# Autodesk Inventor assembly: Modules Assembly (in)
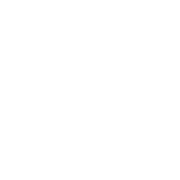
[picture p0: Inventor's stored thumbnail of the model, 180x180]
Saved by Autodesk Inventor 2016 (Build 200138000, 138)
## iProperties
Created: 2014-08
Part Number: Modules Assembly (in)
Document SubType Name: Assembly
Designer: Wally
Author: Wally
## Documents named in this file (1)
- E:\!!AutoCAD Modules!!\!Inventor\Templates\English Templates\Modules Assembly (in).iam
